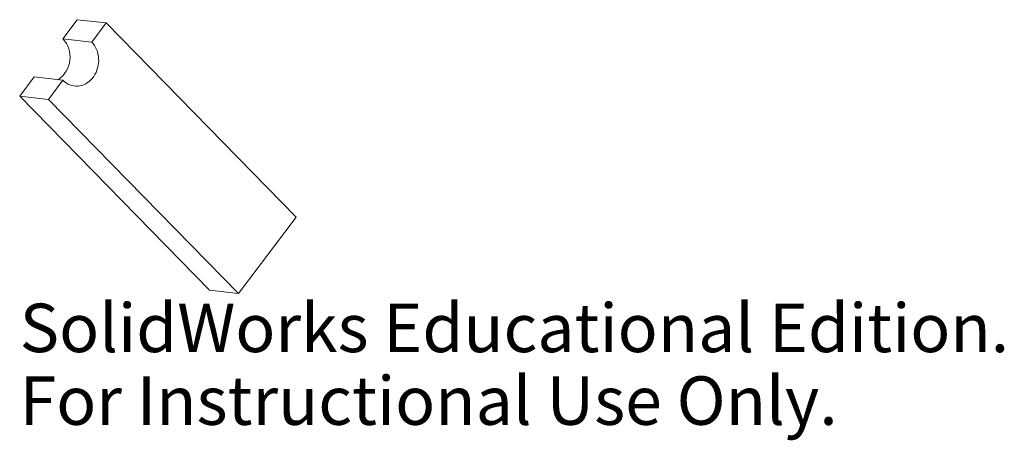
# Model space of a CAD drawing. Units: millimetres. Extents: x -18.9 to 79.2, y -15 to 27.
import ezdxf

# ---------------------------------------------------------------- set-up
doc = ezdxf.new("R2010")
doc.units = ezdxf.units.MM
doc.styles.add('SLDTEXTSTYLE0', font='TXT', dxfattribs={"width": 0.7})

msp = doc.modelspace()

# ---------------------------------------------------------------- linework, layer by layer
at = {"color": 7, "linetype": 'Continuous', "lineweight": 15}
for p, q in [((-13.187, 26.97), (-14.623, 25.065)), ((-10.319, 26.647), (-13.187, 26.97)), ((-10.319, 26.647), (-11.755, 24.742)), ((8.612, 7.296), (-10.319, 26.647)), ((-14.623, 25.065), (-11.755, 24.742)), ((-17.495, 21.256), (-18.931, 19.351)), ((-14.628, 20.933), (-17.495, 21.256)), ((-14.628, 20.933), (-16.064, 19.028)), ((-16.064, 19.028), (-18.931, 19.351)), ((-18.931, 19.351), (0, 0)), ((-16.064, 19.028), (2.867, -0.323)), ((2.867, -0.323), (8.612, 7.296)), ((2.867, -0.323), (0, 0))]:
    msp.add_line(p, q, dxfattribs=at)
at = {"color": 7, "linetype": 'Continuous', "lineweight": 15, "flags": 128}
msp.add_lwpolyline([(-14.628, 20.933), (-14.471, 20.788), (-14.303, 20.662), (-14.125, 20.555), (-13.938, 20.47), (-13.745, 20.405), (-13.547, 20.363), (-13.345, 20.343), (-13.142, 20.346), (-12.94, 20.371), (-12.739, 20.419), (-12.543, 20.488), (-12.353, 20.579), (-12.17, 20.691), (-11.997, 20.821), (-11.834, 20.97), (-11.684, 21.136), (-11.547, 21.317), (-11.426, 21.512), (-11.32, 21.719), (-11.231, 21.936), (-11.16, 22.162), (-11.107, 22.393), (-11.073, 22.629), (-11.059, 22.866), (-11.063, 23.103), (-11.087, 23.338), (-11.13, 23.568), (-11.192, 23.791), (-11.272, 24.006), (-11.369, 24.211), (-11.483, 24.403), (-11.612, 24.58), (-11.755, 24.742)], dxfattribs=at)
at = {"color": 7, "linetype": 'Continuous', "lineweight": 15}
msp.add_arc((-16.653, 23.227), 2.739, 304.99265, 42.15066, dxfattribs=at)

# ---------------------------------------------------------------- texts
at = {"color": 7, "linetype": 'Continuous', "char_height": 4.83362, "attachment_point": 1, "style": 'SLDTEXTSTYLE0'}
for s, insert in [('SolidWorks Educational Edition.', (-18.931, -1.343)), ('For Instructional Use Only.', (-18.931, -8.593))]:
    msp.add_mtext(s, dxfattribs=dict(at, insert=insert))

doc.saveas('drawing.dxf')
